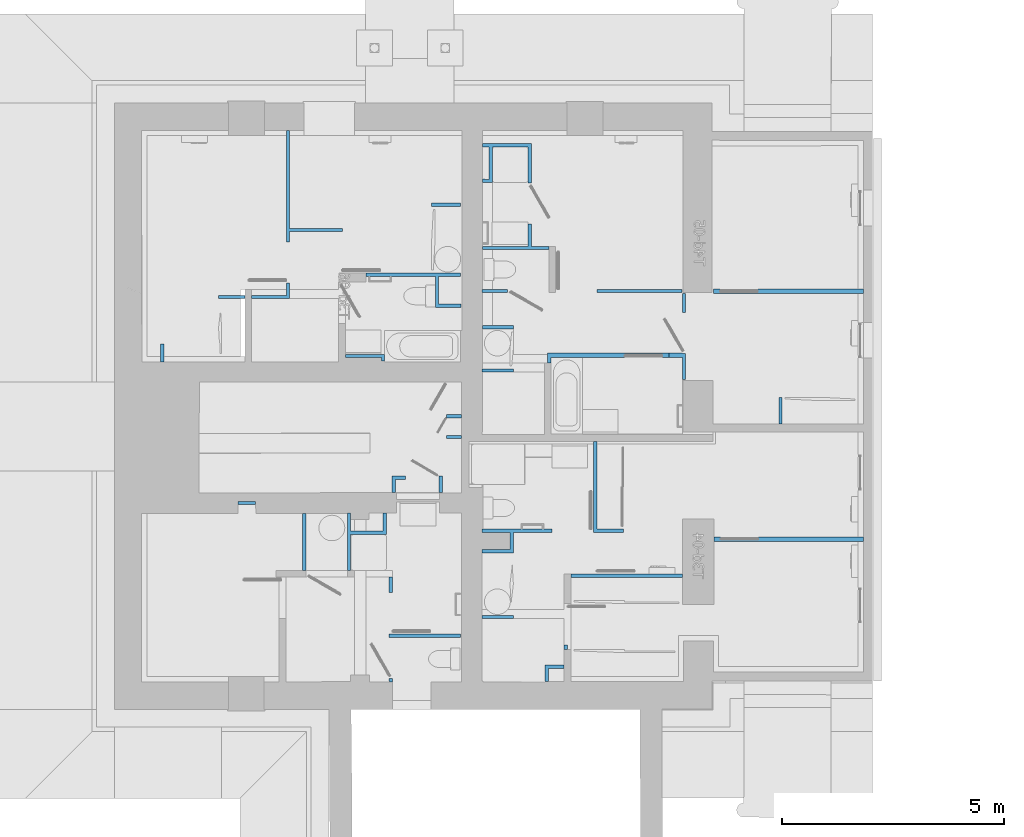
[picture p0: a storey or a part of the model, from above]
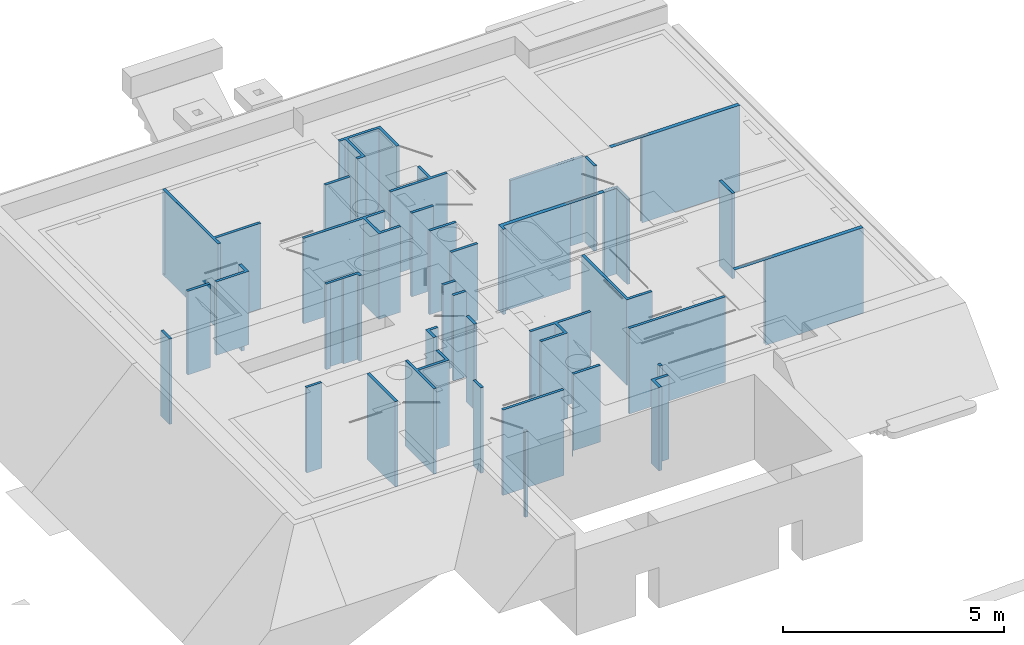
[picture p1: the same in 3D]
Properties of the parts of a building model (IFC4)

# File
Description: ViewDefinition [TrimBim], ExchangeRequirement [Any]
File name: Villa bellevue.ifc
Time: 2023-04-21T16:23:57
Author: infor
Organization: Trimble
Written by: Trimble SketchUp
Made in: Trimble SketchUp
Authorization: IFC4 model

# IfcBuildingElementProxy (56)
Name
8 x Undefined | Undefined - ObjectType: SketchupComponentInstance
4 x ECS | ECS - ObjectType: SketchupComponentInstance
2 x Bloc Baignoire 170 | Bloc Baignoire 170 - ObjectType: SketchupComponentInstance
4 x Bloc WC | Bloc WC - ObjectType: SketchupComponentInstance
5 x Bloc Vasque | Bloc Vasque - ObjectType: SketchupComponentInstance
Undefined | Bloc Douche 1 - ObjectType: SketchupComponentInstance
2 x Bloc Douche 2 | Bloc Douche 2 - ObjectType: SketchupComponentInstance
19 x Undefined | Group - ObjectType: SketchupGroup
Undefined | escalier 2 - ObjectType: SketchupComponentInstance
Undefined | escalier 3 - ObjectType: SketchupComponentInstance
Undefined | Escalier 1 - ObjectType: SketchupComponentInstance
Undefined | escalier 5 - ObjectType: SketchupComponentInstance
Undefined | escalier 4 - ObjectType: SketchupComponentInstance
Undefined | T3d-04 - ObjectType: SketchupComponentInstance
Undefined | T3d-06 - ObjectType: SketchupComponentInstance
Undefined | T4d-05 - ObjectType: SketchupComponentInstance
3 x Undefined | Group - ObjectType: SketchupGroup; ClassProperties - OperationType: single_swing_left; PredefinedType: door

# IfcCovering (2)
Group - ObjectType: SketchupGroup
ClassProperties - PredefinedType: ceiling

# IfcDistributionFlowElement (21)
Name
5 x SS | SS - ObjectType: SketchupComponentInstance
4 x Radiateur R2 73x58 | Radiateur R2 73x58 - ObjectType: SketchupComponentInstance
4 x R2 | R2 - ObjectType: SketchupComponentInstance
2 x Radiateur R3 73x58 | Radiateur R3 73x58 - ObjectType: SketchupComponentInstance
2 x R3 | R3 - ObjectType: SketchupComponentInstance
2 x Radiateur R1 49x58 | Radiateur R1 49x58 - ObjectType: SketchupComponentInstance
2 x R1#1 | R1#1 - ObjectType: SketchupComponentInstance

# IfcDoor (26)
ClassProperties - OperationType: single_swing_left; PredefinedType: door
Name
8 x PP83 | PP83 - ObjectType: SketchupComponentInstance
6 x PP83-2 | PP83-2 - ObjectType: SketchupComponentInstance
3 x Scrigno 80 | Scrigno 80 - ObjectType: SketchupComponentInstance
P PL 06-2 | P PL 06-2 - ObjectType: SketchupComponentInstance
P PL 06-1 | P PL 06-1 - ObjectType: SketchupComponentInstance
P PL 07-1 | P PL 07-1 - ObjectType: SketchupComponentInstance
P PL 04-3 | P PL 04-3 - ObjectType: SketchupComponentInstance
P PL 05-2 | P PL 05-2 - ObjectType: SketchupComponentInstance
P PL 05-1 | P PL 05-1 - ObjectType: SketchupComponentInstance
P PL 04-2 | P PL 04-2 - ObjectType: SketchupComponentInstance
p PL 04-1 | p PL 04-1 - ObjectType: SketchupComponentInstance
Undefined | Group - ObjectType: SketchupGroup

# IfcPlate, Undefined
Group - ObjectType: SketchupGroup
ClassProperties - PredefinedType: ceiling

# IfcWall, Undefined
Group - ObjectType: SketchupGroup
ClassProperties - PredefinedType: ceiling

# IfcWindow (8)
ClassProperties - PartitioningType: single_panel; PredefinedType: window
Name
4 x Men Ext 1 | Men Ext 1 - ObjectType: SketchupComponentInstance
3 x Men Ext 2 | Men Ext 2 - ObjectType: SketchupComponentInstance
Men Ext 3 | Men Ext 3 - ObjectType: SketchupComponentInstance
